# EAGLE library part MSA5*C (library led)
16 Segment, Single Digit Alpha-Numeric Display 0.5 Inch (12.7 mm) Source: www.fairchildsemi.com/ds/MS/MSA5480C.pdf

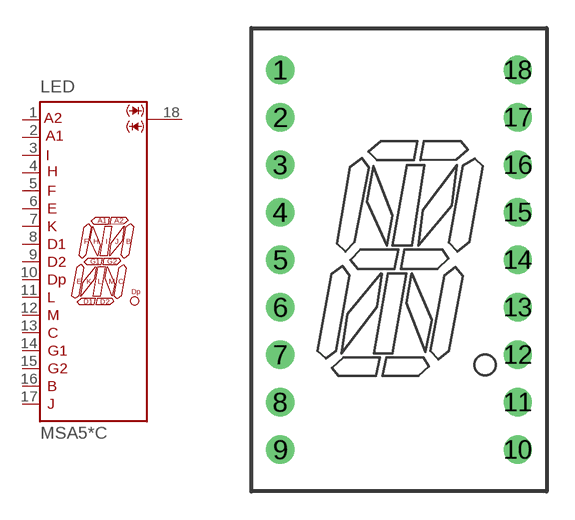
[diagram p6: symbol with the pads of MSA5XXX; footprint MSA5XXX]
Designator prefix LED

## MSA5160C, MSA5180C, MSA5360C, MSA5380C, MSA5460C, MSA5480C, MSA5960C, MSA5980C  [MSA5XXX]
1  1  pas
2  2  pas
3  3  pas
4  4  pas
5  5  pas
6  6  pas
7  7  pas
8  8  pas
9  9  pas
10  10  pas
11  11  pas
12  12  pas
13  13  pas
14  14  pas
15  15  pas
16  16  pas
17  17  pas
18  18  pas

## Footprint MSA5XXX (pad centres in mm)
16 Segment, Single Digit Alpha-Numeric Display 0.5 Inch (12.7 mm) Source: www.fairchildsemi.com/ds/MS/MSA5480C.pdf
drill 1 pad 1.422 round: 1 -6.35,10.16; 2 -6.35,7.62; 3 -6.35,5.08; 4 -6.35,2.54; 5 -6.35,0; 6 -6.35,-2.54; 7 -6.35,-5.08; 8 -6.35,-7.62; 9 -6.35,-10.16; 10 6.35,-10.16; 11 6.35,-7.62; 12 6.35,-5.08; 13 6.35,-2.54; 14 6.35,0; 15 6.35,2.54; 16 6.35,5.08; 17 6.35,7.62; 18 6.35,10.16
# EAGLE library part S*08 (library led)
Kingbright 20mm (0.8Inch) Single Digit Numeric Display Source: SA08-11SRWA.pdf

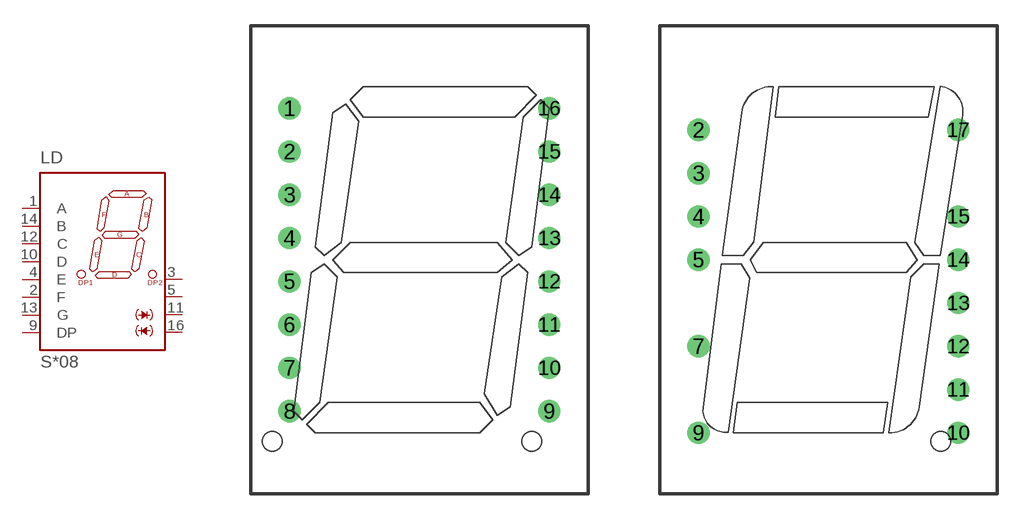
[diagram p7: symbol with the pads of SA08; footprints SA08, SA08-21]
Designator prefix LD

## SA08-11, SC08-11  [SA08]
1  A  pas
2  F  pas
3  AK  pas
4  E  pas
5  AK  pas
9  DP  pas
10  D  pas
11  AK  pas
12  C  pas
13  G  pas
14  B  pas
16  AK  pas

## SA08-12, SC08-12  [SA08]
1  A  pas
2  F  pas
3  AK  pas
4  E  pas
5  AK  pas
6  DP  pas
10  D  pas
11  AK  pas
12  C  pas
13  G  pas
14  B  pas
16  AK  pas

## SC08-21  [SA08-21]
2  A  pas
3  F  pas
4  AK  pas
5  E  pas
9  AK  pas
10  DP  pas
11  D  pas
12  AK  pas
13  C  pas
14  G  pas
15  B  pas
17  AK  pas

## Footprint SA08 (pad centres in mm)
Single Digit Numeric Display 20mm (0.8 Inch) Source: Kingbright .. SA08-11SRWA.pdf
drill 0.8 pad 1.27 round: 1 -7.62,8.89; 2 -7.62,6.35; 3 -7.62,3.81; 4 -7.62,1.27; 5 -7.62,-1.27; 6 -7.62,-3.81; 7 -7.62,-6.35; 8 -7.62,-8.89; 9 7.62,-8.89; 10 7.62,-6.35; 11 7.62,-3.81; 12 7.62,-1.27; 13 7.62,1.27; 14 7.62,3.81; 15 7.62,6.35; 16 7.62,8.89

## Footprint SA08-21 (pad centres in mm)
Single Digit Numeric Display 20mm (0.8 Inch) Source: Kingbright .. SA08-11SRWA.pdf
drill 0.8 pad 1.27 round: 2 -7.62,7.62; 3 -7.62,5.08; 4 -7.62,2.54; 5 -7.62,0; 7 -7.62,-5.08; 9 -7.62,-10.16; 10 7.62,-10.16; 11 7.62,-7.62; 12 7.62,-5.08; 13 7.62,-2.54; 14 7.62,0; 15 7.62,2.54; 17 7.62,7.62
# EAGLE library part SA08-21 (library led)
Kingbright 20mm (0.8Inch) Single Digit Numeric Display Source: SA08-11SRWA.pdf

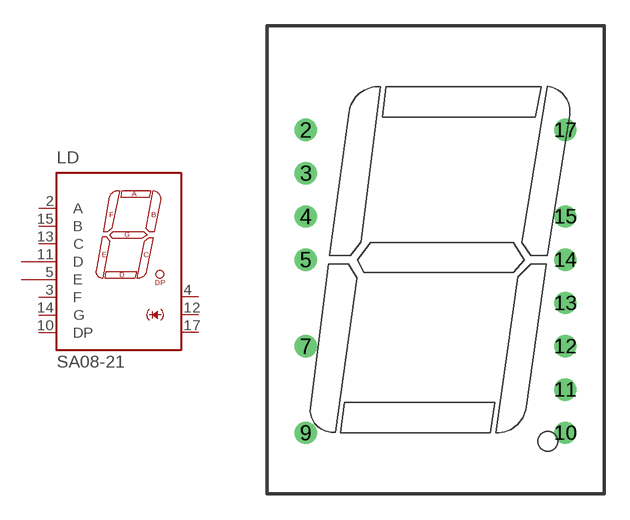
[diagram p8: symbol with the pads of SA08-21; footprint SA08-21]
Designator prefix LD

## SA08-21  [SA08-21]
2  A  pas
3  F  pas
4  AN  pas
5  E  pas
7  E  pas
9  D  pas
10  DP  pas
11  D  pas
12  AN  pas
13  C  pas
14  G  pas
15  B  pas
17  AN  pas

## Footprint SA08-21 (pad centres in mm)
Single Digit Numeric Display 20mm (0.8 Inch) Source: Kingbright .. SA08-11SRWA.pdf
drill 0.8 pad 1.27 round: 2 -7.62,7.62; 3 -7.62,5.08; 4 -7.62,2.54; 5 -7.62,0; 7 -7.62,-5.08; 9 -7.62,-10.16; 10 7.62,-10.16; 11 7.62,-7.62; 12 7.62,-5.08; 13 7.62,-2.54; 14 7.62,0; 15 7.62,2.54; 17 7.62,7.62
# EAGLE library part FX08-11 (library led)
Kingbright 20mm (0.8Inch) Single Digit Numeric Display Source: SA08-11SRWA.pdf

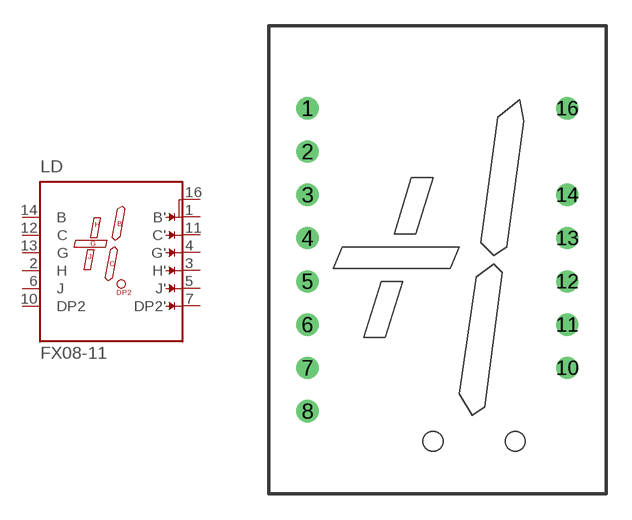
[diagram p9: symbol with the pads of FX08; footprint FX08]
Designator prefix LD

## FX08-11  [FX08]
1  B'  pas
2  H  pas
3  H'  pas
4  G'  pas
5  J'  pas
6  J  pas
7  DP2'  pas
10  DP2  pas
11  C'  pas
12  C  pas
13  G  pas
14  B  pas
16  B_  pas

## Footprint FX08 (pad centres in mm)
Single Digit Numeric Display 20mm (0.8 Inch) Source: Kingbright .. SA08-11SRWA.pdf
drill 0.8 pad 1.27 round: 1 -7.62,8.89; 2 -7.62,6.35; 3 -7.62,3.81; 4 -7.62,1.27; 5 -7.62,-1.27; 6 -7.62,-3.81; 7 -7.62,-6.35; 8 -7.62,-8.89; 10 7.62,-6.35; 11 7.62,-3.81; 12 7.62,-1.27; 13 7.62,1.27; 14 7.62,3.81; 16 7.62,8.89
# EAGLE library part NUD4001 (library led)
High Current LED Driver Source: http://www.onsemi.com/pub/Collateral/NUD4001-D.PDF

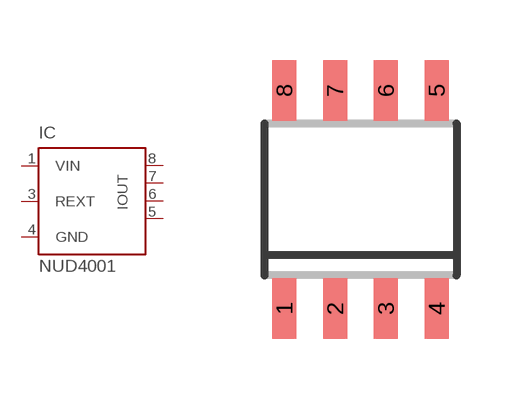
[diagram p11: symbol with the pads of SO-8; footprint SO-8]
Designator prefix IC

## NUD4001  [SO-8]
1  VIN  in
3  REXT  pas
4  GND  pwr
5  IOUT  pas
6  IOUT  pas
7  IOUT  pas
8  IOUT  pas

## Footprint SO-8 (pad centres in mm)
Small Outline Narrow Plastic Gull Wing SO-8 CASE 751-07 150-mil body, package type SN SOurce: http://www.onsemi.com/pub/Collateral/NUD4001-D.PDF
smd 0.6 x 1.52: 1 -1.905,-2.725; 2 -0.635,-2.725; 3 0.635,-2.725; 4 1.905,-2.725; 5 1.905,2.725; 6 0.635,2.725; 7 -0.635,2.725; 8 -1.905,2.725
